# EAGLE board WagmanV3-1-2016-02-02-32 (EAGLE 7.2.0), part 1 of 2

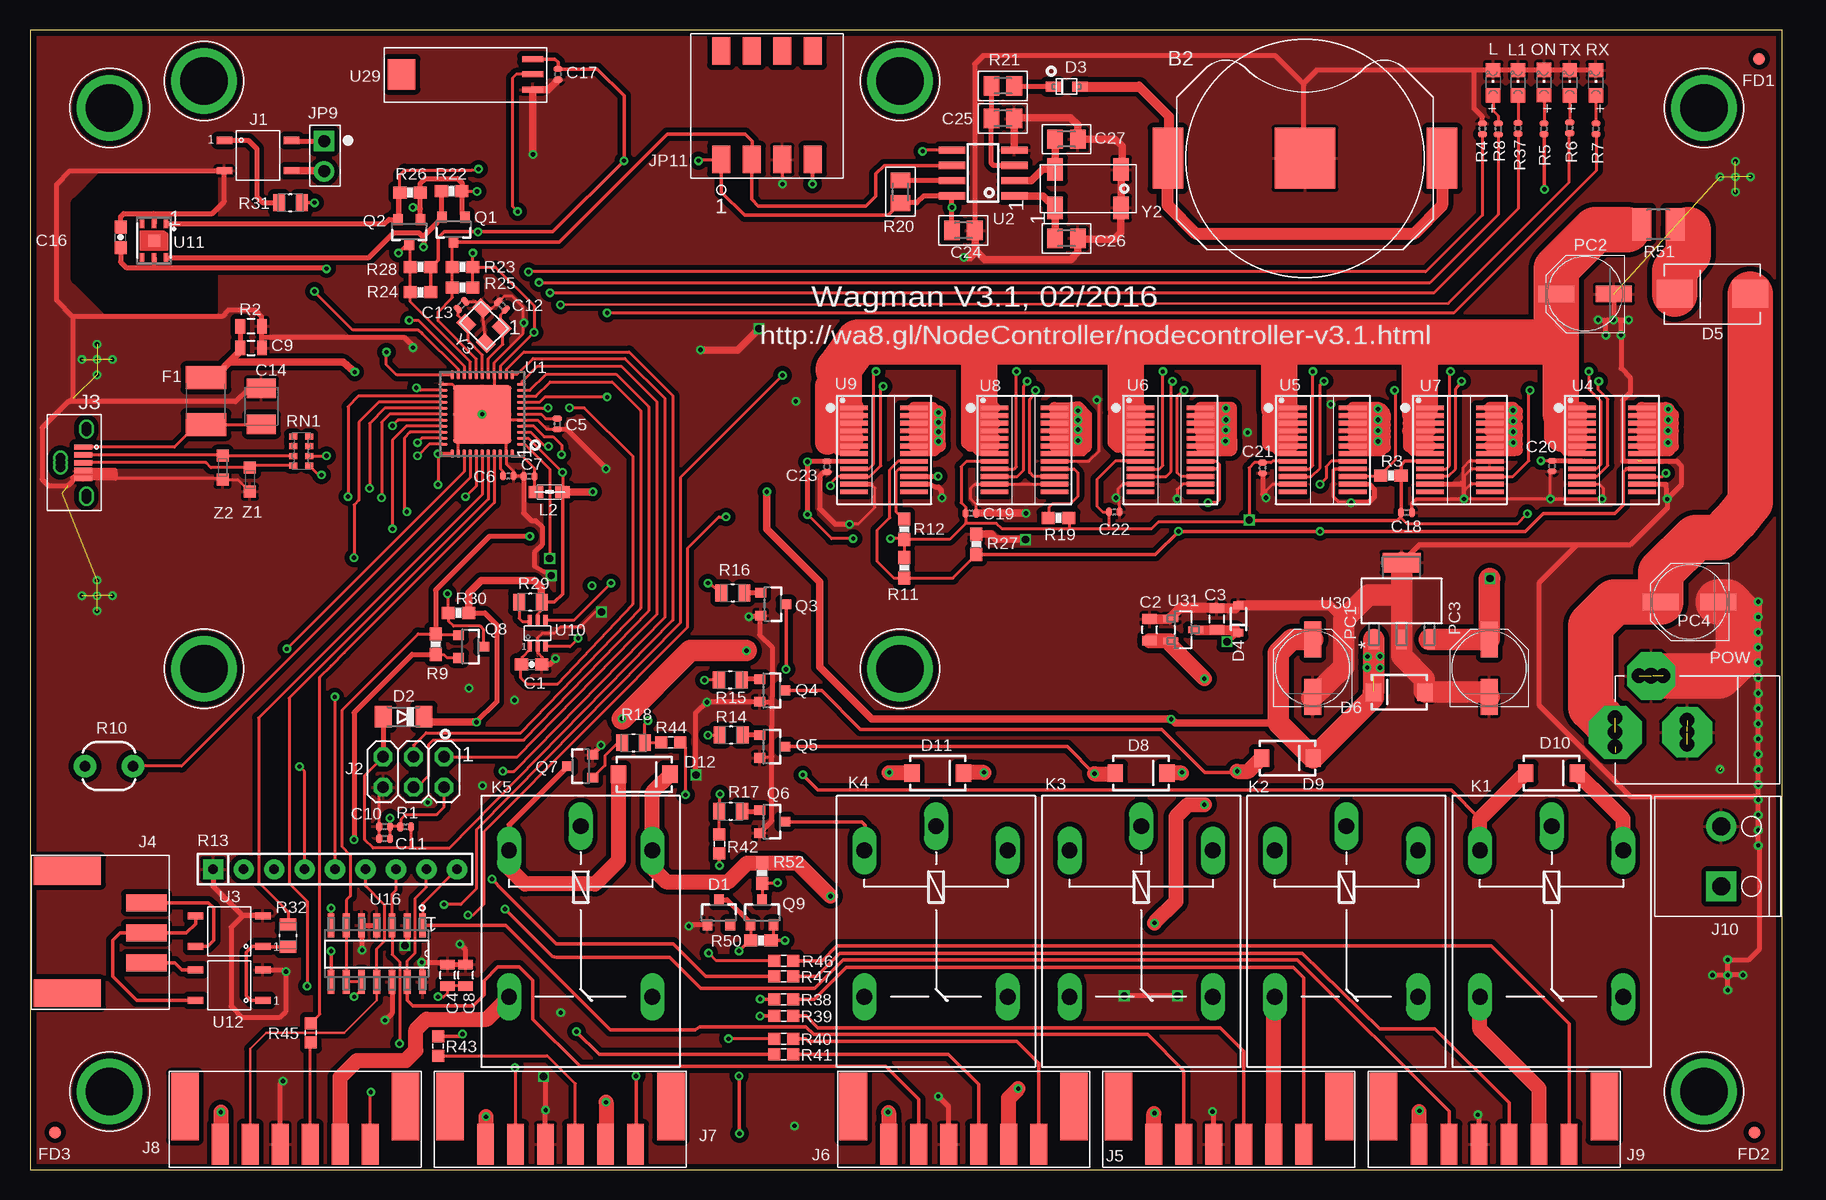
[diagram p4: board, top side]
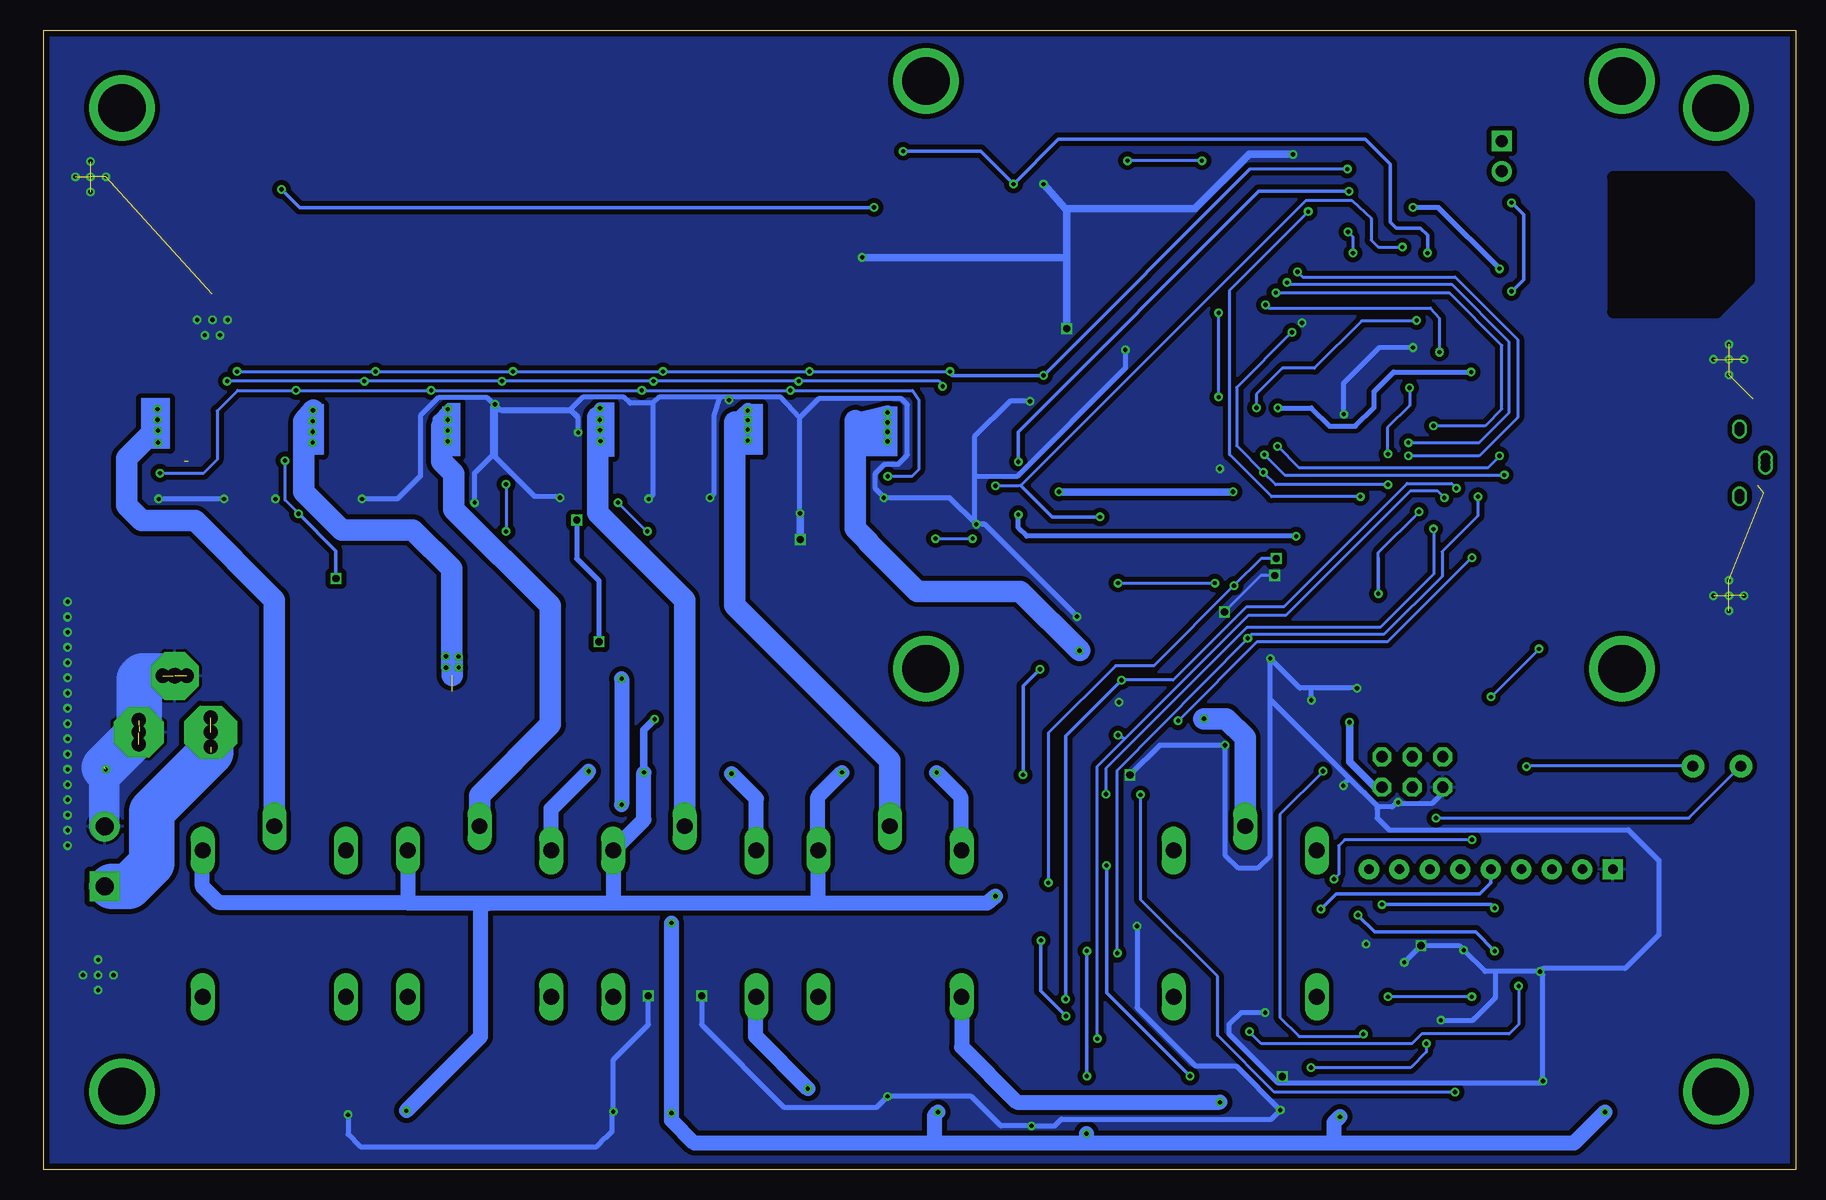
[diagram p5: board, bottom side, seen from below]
Size 146 x 95 mm. Coordinates in mm from the lower left corner, seen from the top.
Outline: 146,95 0,95 0,0 146,0 146,95
Copper layers (1*16): Top 0.035mm / dielectric 1.5mm / Bottom 0.035mm
Design rules "default *": minimum track width 10mil, minimum drill 14mil, track to track 15mil, track to pad 15mil, pad to pad 15mil, via to via 15mil, smd to smd 0mil, copper to edge 20mil, drill to drill 10mil, minimum pad ring 5mil, minimum via ring 5mil, stop-mask expansion 2.5mil, vias tented up to drill 10mil, thermal gap 10mil
Net classes: 0 default: width 0.254 mm, drill 0.61 mm, clearance 0.203 mm
tRestrict: area 3.9,71.5 to 15.1,82.8
bRestrict: area 3.9,71.5 to 15.2,82.7

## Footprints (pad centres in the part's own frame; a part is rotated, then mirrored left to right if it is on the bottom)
BAT-HLD-002-SMT = smd 5.08 x 5.08: NEG 0,0 | smd 2.54 x 5.08: POS1 -11.43,0; POS2 11.43,0
0603-CAP = smd 1.1 x 1: 1 -0.85,0; 2 0.85,0
0805 = smd 0.8 x 1.2: 1 -0.9,0; 2 0.9,0
C0402 = smd 0.508 x 0.762: 1 -0.445,0; 2 0.445,0
SMC_B = smd 1.6 x 2.4: + -1.5,0; - 1.5,0
M0805 = smd 1.3 x 1.6: 1 -0.95,0; 2 0.95,0
SOT23-3 = smd 0.8 x 0.9: 1 -0.95,-1; 2 0.95,-1; 3 0,1.1
MINIMELF = smd 1.4 x 1.8: A 1.7,0; C -1.7,0
SOD-323F = smd 1.27 x 0.813: A -1.118,0; K 1.118,0
SOD-323 = smd 0.63 x 0.83: A 1.15,0; C -1.15,0
DO-214AB = smd 3 x 2.3: A 3.15,0; C -3.15,0
SMA-DIODE = smd 1.27 x 1.47: A -2.15,0; C 2.15,0
L1812 = smd 1.9 x 3.4: 1 -1.95,0; 2 1.95,0
FD-1MM = smd 1 x 1: 1 0,0
SOP-4 = smd 1.3 x 0.6: 1 0,0; 2 0,-2.54; 3 5.6,-2.54; 4 5.6,0
2X03 = drill 0.95 pad 1.55 octagon: 1 -2.54,-1.27; 2 -2.54,1.27; 3 0,-1.27; 4 0,1.27; 5 2.54,-1.27; 6 2.54,1.27
1051330011_MINIUSB_VERTICAL = smd 0.45 x 1.5: 1 -1.3,0; 2 -0.65,0; 3 0,0; 4 0.65,0; 5 1.3,0 | drill 0.8: 6 -2.6,0.25; 7 3,0.25; 8 -3,0.25; 9 -2.8,0.25; 10 2.6,0.25; 11 2.8,0.25; 12 0.4,-1.9; 13 -0.4,-1.9; 14 0,-1.9
3PIN-PTSM-RA-2.5MM = smd 1.4 x 3.4: 1 -2.44,0; 2 0.06,0; 3 2.56,0 | smd 2.3 x 5.6: M1 -5.1,-6.6; M2 5.1,-6.6
6PIN-PTSM-2.5MM = smd 1.4 x 3.4: 1 -6.25,0; 2 -3.75,0; 3 -1.25,0; 4 1.25,0; 5 3.75,0; 6 6.25,0 | smd 2.3 x 5.6: M1 -9.2,-3.15; M2 9.2,-3.15
TB2-5MM = drill 1.5 pad 2.5 square: 1 -2.5,0 | drill 1.5 pad 2.5: 2 2.5,0
CONN_2PIN_P2.54MM = drill 1 pad 1.676 square: 1 0,0 | drill 1 pad 1.676: 2 2.54,0
147721-3 = smd 1.52 x 2.29: 1 0,0; 2 2.54,0; 3 5.08,0; 4 7.62,0; P$5 7.62,9.04; P$6 5.08,9.04; P$7 2.54,9.04; P$8 0,9.04
G5LE = drill 1.321 long: 1 -7.493,-5.969; 2 -7.493,5.969; O 4.699,5.969; P -9.525,0; S 4.699,-5.969
CHIPLED_0805 = smd 1.2 x 1.2: A 0,-1.05; C 0,1.05
0805' = smd 1.2 x 1: 1 -1.1,0; 2 1.1,0
MH3.964 = drill 3.962 pad 5.461: 1 0,0
PANASONIC_D = smd 3 x 1.4: + 2.4,0; - -2.4,0
POWERSUPPLY_DC-21MM = drill 1.2 pad 4.4 octagon: 1 0,-6 | drill 1.2 pad 4.2 octagon: 2 0,0 | drill 1.3 pad 4 octagon: 3 -4.7,-3 | drill 1.2: 4 -4.7,-4; 5 -4.7,-2; 6 -1,0; 7 1,0; 8 -1.2,-6; 9 1.2,-6
R0402 = smd 0.508 x 0.762: 1 -0.445,0; 2 0.445,0
0603-RES = smd 1.1 x 1: 1 -0.85,0; 2 0.85,0
PHOTOCELL-KIT = drill 0.9 pad 1.88: 1 -2,0; 2 2,0
RPACK-SIP-PTH-8-LP = drill 0.8 pad 1.676 square: P$1 0,0 | drill 0.8 pad 1.676: P$2 0,-2.54; P$3 0,-5.08; P$4 0,-7.62; P$5 0,-10.16; P$6 0,-12.7; P$7 0,-15.24; P$8 0,-17.78; P$9 0,-20.32
RESC2013X65N = smd 1.016 x 1.397: 1 -0.94,0; 2 0.94,0
PTC-0603 = smd 1 x 1: 1 -0.8,0; 2 0.8,0
R1210 = smd 1.6 x 2.7: 1 -1.4,0; 2 1.4,0
CAY16 = smd 0.5 x 0.65: 1 -1.2,-0.675; 2 -0.4,-0.675; 3 0.4,-0.675; 4 1.2,-0.675; 5 1.2,0.675; 6 0.4,0.675; 7 -0.4,0.675; 8 -1.2,0.675
QFN44ML7X7 = smd 0.75 x 0.275: 1 -3.275,2.5; 2 -3.275,2; 3 -3.275,1.5; 4 -3.275,1; 5 -3.275,0.5; 6 -3.275,0; 7 -3.275,-0.5; 8 -3.275,-1; 9 -3.275,-1.5; 10 -3.275,-2; 11 -3.275,-2.5; 23 3.275,-2.5; 24 3.275,-2; 25 3.275,-1.5; 26 3.275,-1; 27 3.275,-0.5; 28 3.275,0; 29 3.275,0.5; 30 3.275,1; 31 3.275,1.5; 32 3.275,2; 33 3.275,2.5 | smd 0.275 x 0.75: 12 -2.5,-3.275; 13 -2,-3.275; 14 -1.5,-3.275; 15 -1,-3.275; 16 -0.5,-3.275; 17 0,-3.275; 18 0.5,-3.275; 19 1,-3.275; 20 1.5,-3.275; 21 2,-3.275; 22 2.5,-3.275; 34 2.5,3.275; 35 2,3.275; 36 1.5,3.275; 37 1,3.275; 38 0.5,3.275; 39 0,3.275; 40 -0.5,3.275; 41 -1,3.275; 42 -1.5,3.275; 43 -2,3.275; 44 -2.5,3.275 | smd 4.826 x 4.826: EXP 0,0
SO08 = smd 0.6 x 2.2: 1 -1.905,-2.6; 2 -0.635,-2.6; 3 0.635,-2.6; 4 1.905,-2.6; 5 1.905,2.6; 6 0.635,2.6; 7 -0.635,2.6; 8 -1.905,2.6
QSOP24 = smd 0.4 x 2.3: 1 -3.493,-2.5; 2 -2.857,-2.5; 3 -2.223,-2.5; 4 -1.587,-2.5; 5 -0.953,-2.5; 6 -0.318,-2.5; 7 0.318,-2.5; 8 0.953,-2.5; 9 1.587,-2.5; 10 2.223,-2.5; 11 2.857,-2.5; 12 3.493,-2.5; 13 3.493,2.5; 14 2.857,2.5; 15 2.223,2.5; 16 1.587,2.5; 17 0.953,2.5; 18 0.318,2.5; 19 -0.318,2.5; 20 -0.953,2.5; 21 -1.587,2.5; 22 -2.223,2.5; 23 -2.857,2.5; 24 -3.493,2.5
SOT-363 = smd 0.35 x 0.85: 1 -0.65,-1.1; 2 0,-1.1; 3 0.65,-1.1; 4 0.65,1.1; 5 0,1.1; 6 -0.65,1.1
DD8-3X3MM = smd 0.4 x 0.7: 1 -1,-1.4; 2 0,-1.4; 3 1,-1.4; 4 1,1.4; 5 0,1.4; 6 -1,1.4 | smd 1 x 1: EXP 0,0
SOIC127P600X175-14N = smd 1.981 x 0.559: 1 -2.362,3.81; 2 -2.362,2.54; 3 -2.362,1.27; 4 -2.362,0; 5 -2.362,-1.27; 6 -2.362,-2.54; 7 -2.362,-3.81; 8 2.362,-3.81; 9 2.362,-2.54; 10 2.362,-1.27; 11 2.362,0; 12 2.362,1.27; 13 2.362,2.54; 14 2.362,3.81
HIH4030 = smd 0.51 x 1.78: 1 -1.27,0; 2 0,0; 3 1.27,0 | smd 2.54 x 2.29: 4 0,10.925
SOT230P700X180-4N = smd 1.626 x 0.889: 1 -3.2,2.311; 2 -3.2,0; 3 -3.2,-2.311 | smd 1.626 x 3.175: 4 3.2,0
SOT95P237X112-3N = smd 0.559 x 1.27: 1 -0.94,-1.041; 2 0.94,-1.041; 3 0,1.041
CRYSTAL-CITIZEN-CM2XXC = smd 1.3 x 1.9: P$1 -2.75,-1.6; P$2 2.75,-1.6; P$3 2.75,1.6; P$4 -2.75,1.6
CRYSTAL-3.2-2.5 = smd 1.3 x 1.05: 1 -1.15,-0.925; 2 1.15,-0.925; 3 1.15,0.925; 4 -1.15,0.925
CT/CN0603 = smd 1 x 1: 1 -1,0; 2 1,0

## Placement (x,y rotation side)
B2  CR2016  [BAT-HLD-002-SMT]  106.25,84.3 180 top
C1  100nF  [0603-CAP]  41.8,42.1 0 top
C2  1uF  [0805]  93.3,45 90 top
C3  1uF  [0805]  98.9,45.9 90 top
C4  0.1uF  [0805]  34.8,16.2 90 top
C5  1uF  [C0402]  43.94,62.16 270 top
C6  100n  [C0402]  39.86,57.82 0 top
C7  1uF  [C0402]  41.59,57.79 180 top
C8  10uF  [0805]  36.3,16.2 90 top
C9  100n  [0805]  18.42,68.5 0 top
C10  100n  [C0402]  29.55,28.59 180 top
C11  100n  [C0402]  29.55,27.59 180 top
C12  22pF  [C0402]  39.35,72.02 315 top
C13  22pF  [C0402]  35.96,72.06 225 top
C14  22u  [SMC_B]  19.28,63.62 90 top
C16  100nF  [0603-CAP]  7.55,77.71 90 top
C17  100n  [C0402]  44,91.3 270 top
C18  0.1uF  [C0402]  114.71,54.77 0 top
C19  0.1uF  [C0402]  78.41,54.72 0 top
C20  0.1uF  [C0402]  126.82,58.64 270 top
C21  0.1uF  [C0402]  102.72,58.49 270 top
C22  0.1uF  [C0402]  90.36,54.82 0 top
C23  0.1uF  [C0402]  66.42,58.59 270 top
C24  100nF  [M0805]  77.78,78.29 0 top
C25  100pF  [M0805]  81.07,87.62 0 top
C26  10pF  [M0805]  86.38,77.63 0 top
C27  8.2pF  [M0805]  86.38,85.9 0 top
D1  BZX84C2V4LT1GOSCT-ND  [SOT23-3]  57.4,21.4 0 top
D2  CD1206-S01575  [MINIMELF]  31.13,37.75 180 top
D3  PMEG6002EJ  [SOD-323F]  86.38,90.28 180 top
D4  MM3Z3V6T1GOSCT-ND  [SOD-323]  100.7,45.9 90 top
D5  Dummy_SK106_SK106-TPCT-ND  [DO-214AB]  140.2,73 0 top
D6  SMAZ5V6-FDICT-ND  [SMA-DIODE]  114.1,39.8 180 top
D8  [SMA-DIODE]  92.59,33.05 0 top
D9  [SMA-DIODE]  104.79,34.3 0 top
D10  [SMA-DIODE]  126.79,33.05 0 top
D11  [SMA-DIODE]  75.64,33.05 0 top
D12  [SMA-DIODE]  51.19,32.95 0 top
F1  MF-MSMF050-2 500mA  [L1812]  14.67,64.06 90 top
FD1  FIDUCIAL-1MM  [FD-1MM]  144.1,92.6 180 top
FD2  FIDUCIAL-1MM  [FD-1MM]  143.7,3.1 180 top
FD3  FIDUCIAL-1MM  [FD-1MM]  2.1,3.1 180 top
J1  CPC1125N  [SOP-4]  16.2,85.8 0 top
J2  3x2M  [2X03]  31.97,33.13 180 top
J3  1051330011_MINIUSB  [1051330011_MINIUSB_VERTICAL]  4.45,58.93 270 top
J4  PXC_277-2066-1-ND  [3PIN-PTSM-RA-2.5MM]  9.7,19.8 270 top
J5  PXC-277-2076-1-ND  [6PIN-PTSM-2.5MM]  99.9,2.1 180 top
J6  PXC-277-2076-1-ND  [6PIN-PTSM-2.5MM]  77.8,2.1 180 top
J7  PXC-277-2076-1-ND  [6PIN-PTSM-2.5MM]  44.2,2.1 180 top
J8  PXC-277-2076-1-ND  [6PIN-PTSM-2.5MM]  22.1,2.1 180 top
J9  PXC-277-2076-1-ND  [6PIN-PTSM-2.5MM]  122,2.1 180 top
J10  277-2518-ND  [TB2-5MM]  140.95,26.1 90 top
JP9  [CONN_2PIN_P2.54MM]  24.5,85.75 270 top
JP11  147721-3  [147721-3]  57.6,84.2 0 top
K1  G5LE  [G5LE]  126.8,19.1 270 top
K2  G5LE  [G5LE]  109.7,19.1 270 top
K3  G5LE  [G5LE]  92.6,19.1 270 top
K4  G5LE  [G5LE]  75.5,19.1 270 top
K5  G5LE  [G5LE]  45.89,19.1 270 top
L  green  [CHIPLED_0805]  121.93,90.6 0 top
L1  green  [CHIPLED_0805]  124,90.6 0 top
L2  MH2029-300Y  [0805']  43.28,56.5 180 top
MH1  MH-3.964  [MH3.964]  139.5,88.5 180 top
MH2  MH-3.964  [MH3.964]  139.5,6.51 180 top
MH3  MH-3.964  [MH3.964]  6.64,88.5 180 top
MH4  MH-3.964  [MH3.964]  6.64,6.51 180 top
MH5  MH-3.964  [MH3.964]  72.5,41.75 180 top
MH6  MH-3.964  [MH3.964]  14.5,41.75 180 top
MH7  MH-3.964  [MH3.964]  14.5,90.75 180 top
MH8  MH-3.964  [MH3.964]  72.5,90.75 180 top
ON  blue  [CHIPLED_0805]  126.17,90.61 0 top
PC1  4.7uF  [PANASONIC_D]  106.9,41.8 90 top
PC2  47u  [PANASONIC_D]  129.58,73 180 top
PC3  1uF  [PANASONIC_D]  121.6,41.8 90 top
PC4  47u  [PANASONIC_D]  138.3,47.3 180 top
POW  POWERSUPPLY_DC21MMX  [POWERSUPPLY_DC-21MM]  138.1,36.45 270 top
Q1  BSS138  [SOT23-3]  35.29,78.4 180 top
Q2  BSS138  [SOT23-3]  31.6,78.2 180 top
Q3  MMBT2222A  [SOT23-3]  61.9,47.12 270 top
Q4  MMBT2222A  [SOT23-3]  61.8,39.94 270 top
Q5  MMBT2222A  [SOT23-3]  61.8,35.26 270 top
Q6  MMBT2222A  [SOT23-3]  61.8,29 270 top
Q7  MMBT2222A  [SOT23-3]  45.9,33.62 90 top
Q8  BSS138  [SOT23-3]  36.7,43.6 270 top
Q9  BSS138  [SOT23-3]  61,21.4 0 top
R1  10K  [R0402]  31.3,28.56 0 top
R2  10K  [0805]  18.42,70.3 180 top
R3  22K  [0603-RES]  113.4,57.85 180 top
R4  10K  [R0402]  121.03,86.76 90 top
R5  1K  [R0402]  126.16,86.76 90 top
R6  1K  [R0402]  128.31,86.84 90 top
R7  1K  [R0402]  130.49,86.76 90 top
R8  1K  [R0402]  122.35,86.75 90 top
R9  10K  [0603-RES]  33.8,43.8 270 top
R10  PHOTOCELLPTH-KIT  [PHOTOCELL-KIT]  6.59,33.63 0 top
R11  43K  [0603-RES]  72.85,50.16 270 top
R12  10K  [0603-RES]  72.85,53.38 90 top
R13  23K  [RPACK-SIP-PTH-8-LP]  15.26,25.03 90 top
R14  1K  [RESC2013X65N]  58.43,36.22 180 top
R15  1K  [RESC2013X65N]  58.35,40.82 180 top
R16  1K  [RESC2013X65N]  58.57,48.07 180 top
R17  1K  [RESC2013X65N]  58.39,29.87 180 top
R18  1K  [RESC2013X65N]  50.29,35.58 0 top
R19  10K  [0603-RES]  85.71,54.31 180 top
R20  10K  [M0805]  72.54,81.51 270 top
R21  1K  [M0805]  81.07,90.34 0 top
R22  10K  [0603-RES]  35.14,81.55 180 top
R23  10K  [0603-RES]  36.04,75.24 180 top
R24  4.7K  [0603-RES]  32.54,73.13 0 top
R25  4.7K  [0603-RES]  36.04,73.53 0 top
R26  10K  [0603-RES]  31.68,81.45 180 top
R27  54K  [0603-RES]  78.85,52.11 90 top
R28  10K  [0603-RES]  32.54,75.24 180 top
R29  1K  [RESC2013X65N]  41.7,47.3 0 top
R30  10K  [0603-RES]  35.7,46.4 180 top
R31  150R  [RESC2013X65N]  21.7,80.6 0 top
R32  150R  [RESC2013X65N]  21.5,19.5 90 top
R37  1K  [R0402]  124,86.8 90 top
R38  PRG18BB470MB1RB  [PTC-0603]  62.8,14.2 180 top
R39  PRG18BB470MB1RB  [PTC-0603]  62.8,12.8 180 top
R40  PRG18BB470MB1RB  [PTC-0603]  62.8,10.9 180 top
R41  PRG18BB470MB1RB  [PTC-0603]  62.8,9.6 180 top
R42  PRG18BB470MB1RB  [PTC-0603]  57.45,27.15 90 top
R43  PRG18BB470MB1RB  [PTC-0603]  34,10.3 90 top
R44  PRG18BB470MB1RB  [PTC-0603]  53.4,35.6 180 top
R45  PRG18BB470MB1RB  [PTC-0603]  23.4,11.4 90 top
R46  PRG18BB470MB1RB  [PTC-0603]  62.8,17.4 180 top
R47  PRG18BB470MB1RB  [PTC-0603]  62.8,16.1 180 top
R50  10K  [0603-RES]  60.9,19.1 0 top
R51  BLE32P  [R1210]  135.7,78.8 180 top
R52  10K  [0603-RES]  61,24.7 270 top
RN1  22R  [CAY16]  22.6,59.9 90 top
RX  yellow  [CHIPLED_0805]  130.49,90.6 0 top
TX  yellow  [CHIPLED_0805]  128.31,90.6 0 top
U1  ATMEGA32U4-XUMU  [QFN44ML7X7]  37.69,62.96 180 top
U2  MCP79412  [SO08]  79.43,83.07 90 top
U3  CPC1125N  [SOP-4]  19.4,18.6 180 top
U4  ACS764-QSOP24  [QSOP24]  131.82,60 270 top
U5  ACS764-QSOP24  [QSOP24]  107.73,60 270 top
U6  ACS764-QSOP24  [QSOP24]  95.04,60 270 top
U7  ACS764-QSOP24  [QSOP24]  119.15,60 270 top
U8  ACS764-QSOP24  [QSOP24]  82.86,60 270 top
U9  ACS764-QSOP24  [QSOP24]  71.17,60 270 top
U10  SN74LVC1G175DCKR  [SOT-363]  42.3,44.7 0 top
U11  HTU21D  [DD8-3X3MM]  10.34,77.44 180 top
U12  CPC1017N  [SOP-4]  19.4,14.1 180 top
U16  MCP3428-E/SL  [SOIC127P600X175-14N]  28.9,18 270 top
U29  HIH4030  [HIH4030]  41.9,91.3 90 top
U30  MCP1825S-3302E/DB  [SOT230P700X180-4N]  114.3,47.4 90 top
U31  MCP1700T-1802E/TT  [SOT95P237X112-3N]  96.1,45 270 top
Y2  32.768 kHz  [CRYSTAL-CITIZEN-CM2XXC]  88.18,81.77 0 top
Y3  16MHz KX-7  [CRYSTAL-3.2-2.5]  37.83,70.35 135 top
Z1  CG0603MLC-05E  [CT/CN0603]  18.33,57.52 270 top
Z2  CG0603MLC-05E  [CT/CN0603]  16.06,58.52 270 top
